VERSION 5.7 ;
BUSBITCHARS "[]" ;
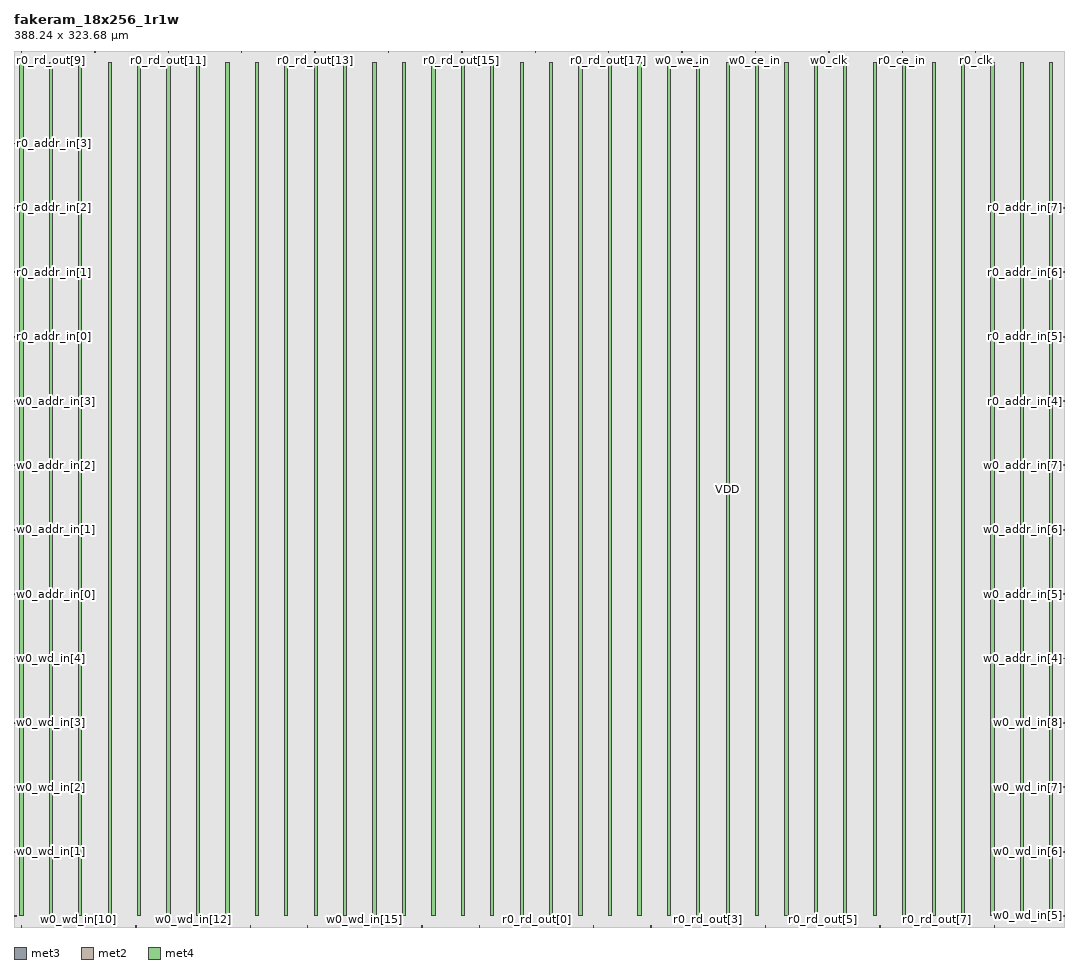
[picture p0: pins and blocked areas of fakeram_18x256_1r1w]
MACRO fakeram_18x256_1r1w
  FOREIGN fakeram_18x256_1r1w 0 0 ;
  SYMMETRY X Y R90 ;
  SIZE 388.240 BY 323.680 ;
  CLASS BLOCK ;
  PIN w0_wd_in[0]
    DIRECTION INPUT ;
    USE SIGNAL ;
    SHAPE ABUTMENT ;
    PORT
      LAYER met3 ;
      RECT 0.000 3.930 0.900 4.230 ;
    END
  END w0_wd_in[0]
  PIN w0_wd_in[1]
    DIRECTION INPUT ;
    USE SIGNAL ;
    SHAPE ABUTMENT ;
    PORT
      LAYER met3 ;
      RECT 0.000 27.730 0.900 28.030 ;
    END
  END w0_wd_in[1]
  PIN w0_wd_in[2]
    DIRECTION INPUT ;
    USE SIGNAL ;
    SHAPE ABUTMENT ;
    PORT
      LAYER met3 ;
      RECT 0.000 51.530 0.900 51.830 ;
    END
  END w0_wd_in[2]
  PIN w0_wd_in[3]
    DIRECTION INPUT ;
    USE SIGNAL ;
    SHAPE ABUTMENT ;
    PORT
      LAYER met3 ;
      RECT 0.000 75.330 0.900 75.630 ;
    END
  END w0_wd_in[3]
  PIN w0_wd_in[4]
    DIRECTION INPUT ;
    USE SIGNAL ;
    SHAPE ABUTMENT ;
    PORT
      LAYER met3 ;
      RECT 0.000 99.130 0.900 99.430 ;
    END
  END w0_wd_in[4]
  PIN w0_wd_in[5]
    DIRECTION INPUT ;
    USE SIGNAL ;
    SHAPE ABUTMENT ;
    PORT
      LAYER met3 ;
      RECT 387.340 3.930 388.240 4.230 ;
    END
  END w0_wd_in[5]
  PIN w0_wd_in[6]
    DIRECTION INPUT ;
    USE SIGNAL ;
    SHAPE ABUTMENT ;
    PORT
      LAYER met3 ;
      RECT 387.340 27.730 388.240 28.030 ;
    END
  END w0_wd_in[6]
  PIN w0_wd_in[7]
    DIRECTION INPUT ;
    USE SIGNAL ;
    SHAPE ABUTMENT ;
    PORT
      LAYER met3 ;
      RECT 387.340 51.530 388.240 51.830 ;
    END
  END w0_wd_in[7]
  PIN w0_wd_in[8]
    DIRECTION INPUT ;
    USE SIGNAL ;
    SHAPE ABUTMENT ;
    PORT
      LAYER met3 ;
      RECT 387.340 75.330 388.240 75.630 ;
    END
  END w0_wd_in[8]
  PIN w0_wd_in[9]
    DIRECTION OUTPUT ;
    USE SIGNAL ;
    SHAPE ABUTMENT ;
    PORT
      LAYER met2 ;
      RECT 2.690 0.000 2.830 0.420 ;
    END
  END w0_wd_in[9]
  PIN w0_wd_in[10]
    DIRECTION OUTPUT ;
    USE SIGNAL ;
    SHAPE ABUTMENT ;
    PORT
      LAYER met2 ;
      RECT 23.850 0.000 23.990 0.420 ;
    END
  END w0_wd_in[10]
  PIN w0_wd_in[11]
    DIRECTION OUTPUT ;
    USE SIGNAL ;
    SHAPE ABUTMENT ;
    PORT
      LAYER met2 ;
      RECT 45.010 0.000 45.150 0.420 ;
    END
  END w0_wd_in[11]
  PIN w0_wd_in[12]
    DIRECTION OUTPUT ;
    USE SIGNAL ;
    SHAPE ABUTMENT ;
    PORT
      LAYER met2 ;
      RECT 66.170 0.000 66.310 0.420 ;
    END
  END w0_wd_in[12]
  PIN w0_wd_in[13]
    DIRECTION OUTPUT ;
    USE SIGNAL ;
    SHAPE ABUTMENT ;
    PORT
      LAYER met2 ;
      RECT 87.330 0.000 87.470 0.420 ;
    END
  END w0_wd_in[13]
  PIN w0_wd_in[14]
    DIRECTION OUTPUT ;
    USE SIGNAL ;
    SHAPE ABUTMENT ;
    PORT
      LAYER met2 ;
      RECT 108.490 0.000 108.630 0.420 ;
    END
  END w0_wd_in[14]
  PIN w0_wd_in[15]
    DIRECTION OUTPUT ;
    USE SIGNAL ;
    SHAPE ABUTMENT ;
    PORT
      LAYER met2 ;
      RECT 129.650 0.000 129.790 0.420 ;
    END
  END w0_wd_in[15]
  PIN w0_wd_in[16]
    DIRECTION OUTPUT ;
    USE SIGNAL ;
    SHAPE ABUTMENT ;
    PORT
      LAYER met2 ;
      RECT 150.810 0.000 150.950 0.420 ;
    END
  END w0_wd_in[16]
  PIN w0_wd_in[17]
    DIRECTION OUTPUT ;
    USE SIGNAL ;
    SHAPE ABUTMENT ;
    PORT
      LAYER met2 ;
      RECT 171.970 0.000 172.110 0.420 ;
    END
  END w0_wd_in[17]
  PIN r0_rd_out[0]
    DIRECTION OUTPUT ;
    USE SIGNAL ;
    SHAPE ABUTMENT ;
    PORT
      LAYER met2 ;
      RECT 193.130 0.000 193.270 0.420 ;
    END
  END r0_rd_out[0]
  PIN r0_rd_out[1]
    DIRECTION OUTPUT ;
    USE SIGNAL ;
    SHAPE ABUTMENT ;
    PORT
      LAYER met2 ;
      RECT 214.290 0.000 214.430 0.420 ;
    END
  END r0_rd_out[1]
  PIN r0_rd_out[2]
    DIRECTION OUTPUT ;
    USE SIGNAL ;
    SHAPE ABUTMENT ;
    PORT
      LAYER met2 ;
      RECT 235.450 0.000 235.590 0.420 ;
    END
  END r0_rd_out[2]
  PIN r0_rd_out[3]
    DIRECTION OUTPUT ;
    USE SIGNAL ;
    SHAPE ABUTMENT ;
    PORT
      LAYER met2 ;
      RECT 256.610 0.000 256.750 0.420 ;
    END
  END r0_rd_out[3]
  PIN r0_rd_out[4]
    DIRECTION OUTPUT ;
    USE SIGNAL ;
    SHAPE ABUTMENT ;
    PORT
      LAYER met2 ;
      RECT 277.770 0.000 277.910 0.420 ;
    END
  END r0_rd_out[4]
  PIN r0_rd_out[5]
    DIRECTION OUTPUT ;
    USE SIGNAL ;
    SHAPE ABUTMENT ;
    PORT
      LAYER met2 ;
      RECT 298.930 0.000 299.070 0.420 ;
    END
  END r0_rd_out[5]
  PIN r0_rd_out[6]
    DIRECTION OUTPUT ;
    USE SIGNAL ;
    SHAPE ABUTMENT ;
    PORT
      LAYER met2 ;
      RECT 320.090 0.000 320.230 0.420 ;
    END
  END r0_rd_out[6]
  PIN r0_rd_out[7]
    DIRECTION OUTPUT ;
    USE SIGNAL ;
    SHAPE ABUTMENT ;
    PORT
      LAYER met2 ;
      RECT 341.250 0.000 341.390 0.420 ;
    END
  END r0_rd_out[7]
  PIN r0_rd_out[8]
    DIRECTION OUTPUT ;
    USE SIGNAL ;
    SHAPE ABUTMENT ;
    PORT
      LAYER met2 ;
      RECT 362.410 0.000 362.550 0.420 ;
    END
  END r0_rd_out[8]
  PIN r0_rd_out[9]
    DIRECTION OUTPUT ;
    USE SIGNAL ;
    SHAPE ABUTMENT ;
    PORT
      LAYER met2 ;
      RECT 2.690 323.260 2.830 323.680 ;
    END
  END r0_rd_out[9]
  PIN r0_rd_out[10]
    DIRECTION OUTPUT ;
    USE SIGNAL ;
    SHAPE ABUTMENT ;
    PORT
      LAYER met2 ;
      RECT 29.830 323.260 29.970 323.680 ;
    END
  END r0_rd_out[10]
  PIN r0_rd_out[11]
    DIRECTION OUTPUT ;
    USE SIGNAL ;
    SHAPE ABUTMENT ;
    PORT
      LAYER met2 ;
      RECT 56.970 323.260 57.110 323.680 ;
    END
  END r0_rd_out[11]
  PIN r0_rd_out[12]
    DIRECTION OUTPUT ;
    USE SIGNAL ;
    SHAPE ABUTMENT ;
    PORT
      LAYER met2 ;
      RECT 84.110 323.260 84.250 323.680 ;
    END
  END r0_rd_out[12]
  PIN r0_rd_out[13]
    DIRECTION OUTPUT ;
    USE SIGNAL ;
    SHAPE ABUTMENT ;
    PORT
      LAYER met2 ;
      RECT 111.250 323.260 111.390 323.680 ;
    END
  END r0_rd_out[13]
  PIN r0_rd_out[14]
    DIRECTION OUTPUT ;
    USE SIGNAL ;
    SHAPE ABUTMENT ;
    PORT
      LAYER met2 ;
      RECT 138.390 323.260 138.530 323.680 ;
    END
  END r0_rd_out[14]
  PIN r0_rd_out[15]
    DIRECTION OUTPUT ;
    USE SIGNAL ;
    SHAPE ABUTMENT ;
    PORT
      LAYER met2 ;
      RECT 165.530 323.260 165.670 323.680 ;
    END
  END r0_rd_out[15]
  PIN r0_rd_out[16]
    DIRECTION OUTPUT ;
    USE SIGNAL ;
    SHAPE ABUTMENT ;
    PORT
      LAYER met2 ;
      RECT 192.670 323.260 192.810 323.680 ;
    END
  END r0_rd_out[16]
  PIN r0_rd_out[17]
    DIRECTION OUTPUT ;
    USE SIGNAL ;
    SHAPE ABUTMENT ;
    PORT
      LAYER met2 ;
      RECT 219.810 323.260 219.950 323.680 ;
    END
  END r0_rd_out[17]
  PIN w0_addr_in[0]
    DIRECTION INPUT ;
    USE SIGNAL ;
    SHAPE ABUTMENT ;
    PORT
      LAYER met3 ;
      RECT 0.000 122.930 0.900 123.230 ;
    END
  END w0_addr_in[0]
  PIN w0_addr_in[1]
    DIRECTION INPUT ;
    USE SIGNAL ;
    SHAPE ABUTMENT ;
    PORT
      LAYER met3 ;
      RECT 0.000 146.730 0.900 147.030 ;
    END
  END w0_addr_in[1]
  PIN w0_addr_in[2]
    DIRECTION INPUT ;
    USE SIGNAL ;
    SHAPE ABUTMENT ;
    PORT
      LAYER met3 ;
      RECT 0.000 170.530 0.900 170.830 ;
    END
  END w0_addr_in[2]
  PIN w0_addr_in[3]
    DIRECTION INPUT ;
    USE SIGNAL ;
    SHAPE ABUTMENT ;
    PORT
      LAYER met3 ;
      RECT 0.000 194.330 0.900 194.630 ;
    END
  END w0_addr_in[3]
  PIN w0_addr_in[4]
    DIRECTION INPUT ;
    USE SIGNAL ;
    SHAPE ABUTMENT ;
    PORT
      LAYER met3 ;
      RECT 387.340 99.130 388.240 99.430 ;
    END
  END w0_addr_in[4]
  PIN w0_addr_in[5]
    DIRECTION INPUT ;
    USE SIGNAL ;
    SHAPE ABUTMENT ;
    PORT
      LAYER met3 ;
      RECT 387.340 122.930 388.240 123.230 ;
    END
  END w0_addr_in[5]
  PIN w0_addr_in[6]
    DIRECTION INPUT ;
    USE SIGNAL ;
    SHAPE ABUTMENT ;
    PORT
      LAYER met3 ;
      RECT 387.340 146.730 388.240 147.030 ;
    END
  END w0_addr_in[6]
  PIN w0_addr_in[7]
    DIRECTION INPUT ;
    USE SIGNAL ;
    SHAPE ABUTMENT ;
    PORT
      LAYER met3 ;
      RECT 387.340 170.530 388.240 170.830 ;
    END
  END w0_addr_in[7]
  PIN r0_addr_in[0]
    DIRECTION INPUT ;
    USE SIGNAL ;
    SHAPE ABUTMENT ;
    PORT
      LAYER met3 ;
      RECT 0.000 218.130 0.900 218.430 ;
    END
  END r0_addr_in[0]
  PIN r0_addr_in[1]
    DIRECTION INPUT ;
    USE SIGNAL ;
    SHAPE ABUTMENT ;
    PORT
      LAYER met3 ;
      RECT 0.000 241.930 0.900 242.230 ;
    END
  END r0_addr_in[1]
  PIN r0_addr_in[2]
    DIRECTION INPUT ;
    USE SIGNAL ;
    SHAPE ABUTMENT ;
    PORT
      LAYER met3 ;
      RECT 0.000 265.730 0.900 266.030 ;
    END
  END r0_addr_in[2]
  PIN r0_addr_in[3]
    DIRECTION INPUT ;
    USE SIGNAL ;
    SHAPE ABUTMENT ;
    PORT
      LAYER met3 ;
      RECT 0.000 289.530 0.900 289.830 ;
    END
  END r0_addr_in[3]
  PIN r0_addr_in[4]
    DIRECTION INPUT ;
    USE SIGNAL ;
    SHAPE ABUTMENT ;
    PORT
      LAYER met3 ;
      RECT 387.340 194.330 388.240 194.630 ;
    END
  END r0_addr_in[4]
  PIN r0_addr_in[5]
    DIRECTION INPUT ;
    USE SIGNAL ;
    SHAPE ABUTMENT ;
    PORT
      LAYER met3 ;
      RECT 387.340 218.130 388.240 218.430 ;
    END
  END r0_addr_in[5]
  PIN r0_addr_in[6]
    DIRECTION INPUT ;
    USE SIGNAL ;
    SHAPE ABUTMENT ;
    PORT
      LAYER met3 ;
      RECT 387.340 241.930 388.240 242.230 ;
    END
  END r0_addr_in[6]
  PIN r0_addr_in[7]
    DIRECTION INPUT ;
    USE SIGNAL ;
    SHAPE ABUTMENT ;
    PORT
      LAYER met3 ;
      RECT 387.340 265.730 388.240 266.030 ;
    END
  END r0_addr_in[7]
  PIN w0_we_in
    DIRECTION INPUT ;
    USE SIGNAL ;
    SHAPE ABUTMENT ;
    PORT
      LAYER met2 ;
      RECT 246.950 323.260 247.090 323.680 ;
    END
  END w0_we_in
  PIN w0_ce_in
    DIRECTION INPUT ;
    USE SIGNAL ;
    SHAPE ABUTMENT ;
    PORT
      LAYER met2 ;
      RECT 274.090 323.260 274.230 323.680 ;
    END
  END w0_ce_in
  PIN w0_clk
    DIRECTION INPUT ;
    USE SIGNAL ;
    SHAPE ABUTMENT ;
    PORT
      LAYER met2 ;
      RECT 301.230 323.260 301.370 323.680 ;
    END
  END w0_clk
  PIN r0_ce_in
    DIRECTION INPUT ;
    USE SIGNAL ;
    SHAPE ABUTMENT ;
    PORT
      LAYER met2 ;
      RECT 328.370 323.260 328.510 323.680 ;
    END
  END r0_ce_in
  PIN r0_clk
    DIRECTION INPUT ;
    USE SIGNAL ;
    SHAPE ABUTMENT ;
    PORT
      LAYER met2 ;
      RECT 355.510 323.260 355.650 323.680 ;
    END
  END r0_clk
  PIN VSS
    DIRECTION INOUT ;
    USE GROUND ;
    PORT
      LAYER met4 ;
      RECT 2.160 4.080 3.360 319.600 ;
      RECT 13.040 4.080 14.240 319.600 ;
      RECT 23.920 4.080 25.120 319.600 ;
      RECT 34.800 4.080 36.000 319.600 ;
      RECT 45.680 4.080 46.880 319.600 ;
      RECT 56.560 4.080 57.760 319.600 ;
      RECT 67.440 4.080 68.640 319.600 ;
      RECT 78.320 4.080 79.520 319.600 ;
      RECT 89.200 4.080 90.400 319.600 ;
      RECT 100.080 4.080 101.280 319.600 ;
      RECT 110.960 4.080 112.160 319.600 ;
      RECT 121.840 4.080 123.040 319.600 ;
      RECT 132.720 4.080 133.920 319.600 ;
      RECT 143.600 4.080 144.800 319.600 ;
      RECT 154.480 4.080 155.680 319.600 ;
      RECT 165.360 4.080 166.560 319.600 ;
      RECT 176.240 4.080 177.440 319.600 ;
      RECT 187.120 4.080 188.320 319.600 ;
      RECT 198.000 4.080 199.200 319.600 ;
      RECT 208.880 4.080 210.080 319.600 ;
      RECT 219.760 4.080 220.960 319.600 ;
      RECT 230.640 4.080 231.840 319.600 ;
      RECT 241.520 4.080 242.720 319.600 ;
      RECT 252.400 4.080 253.600 319.600 ;
      RECT 263.280 4.080 264.480 319.600 ;
      RECT 274.160 4.080 275.360 319.600 ;
      RECT 285.040 4.080 286.240 319.600 ;
      RECT 295.920 4.080 297.120 319.600 ;
      RECT 306.800 4.080 308.000 319.600 ;
      RECT 317.680 4.080 318.880 319.600 ;
      RECT 328.560 4.080 329.760 319.600 ;
      RECT 339.440 4.080 340.640 319.600 ;
      RECT 350.320 4.080 351.520 319.600 ;
      RECT 361.200 4.080 362.400 319.600 ;
      RECT 372.080 4.080 373.280 319.600 ;
      RECT 382.960 4.080 384.160 319.600 ;
    END
  END VSS
  PIN VDD
    DIRECTION INOUT ;
    USE POWER ;
    PORT
      LAYER met4 ;
      RECT 2.160 4.080 3.360 319.600 ;
      RECT 13.040 4.080 14.240 319.600 ;
      RECT 23.920 4.080 25.120 319.600 ;
      RECT 34.800 4.080 36.000 319.600 ;
      RECT 45.680 4.080 46.880 319.600 ;
      RECT 56.560 4.080 57.760 319.600 ;
      RECT 67.440 4.080 68.640 319.600 ;
      RECT 78.320 4.080 79.520 319.600 ;
      RECT 89.200 4.080 90.400 319.600 ;
      RECT 100.080 4.080 101.280 319.600 ;
      RECT 110.960 4.080 112.160 319.600 ;
      RECT 121.840 4.080 123.040 319.600 ;
      RECT 132.720 4.080 133.920 319.600 ;
      RECT 143.600 4.080 144.800 319.600 ;
      RECT 154.480 4.080 155.680 319.600 ;
      RECT 165.360 4.080 166.560 319.600 ;
      RECT 176.240 4.080 177.440 319.600 ;
      RECT 187.120 4.080 188.320 319.600 ;
      RECT 198.000 4.080 199.200 319.600 ;
      RECT 208.880 4.080 210.080 319.600 ;
      RECT 219.760 4.080 220.960 319.600 ;
      RECT 230.640 4.080 231.840 319.600 ;
      RECT 241.520 4.080 242.720 319.600 ;
      RECT 252.400 4.080 253.600 319.600 ;
      RECT 263.280 4.080 264.480 319.600 ;
      RECT 274.160 4.080 275.360 319.600 ;
      RECT 285.040 4.080 286.240 319.600 ;
      RECT 295.920 4.080 297.120 319.600 ;
      RECT 306.800 4.080 308.000 319.600 ;
      RECT 317.680 4.080 318.880 319.600 ;
      RECT 328.560 4.080 329.760 319.600 ;
      RECT 339.440 4.080 340.640 319.600 ;
      RECT 350.320 4.080 351.520 319.600 ;
      RECT 361.200 4.080 362.400 319.600 ;
      RECT 372.080 4.080 373.280 319.600 ;
      RECT 382.960 4.080 384.160 319.600 ;
    END
  END VDD
  OBS
    LAYER met1 ;
    RECT 0 0 388.240 323.680 ;
    LAYER met2 ;
    RECT 0 0 388.240 323.680 ;
    LAYER met3 ;
    RECT 0 0 388.240 323.680 ;
    LAYER met4 ;
    RECT 0 0 388.240 323.680 ;
  END
END fakeram_18x256_1r1w

END LIBRARY
